(* Logix 5000 AddOnInstructionDefinition export Banner_B25_Param_v4; software revision 33.03; part 2 of 2 *)
(* tags used below, declared in another part *)
   B25 : Banner_B25_v4;
   Port_Data : Banner_IOL_Port_v4;
   Port : DINT;
   Local_Control : DINT;
   Command_Being_Processed : BOOL;
   Index_Write_Inprocess : INT;
   Inprocess_Index : DINT;
(* Banner_B25_Param_v4, continued *)

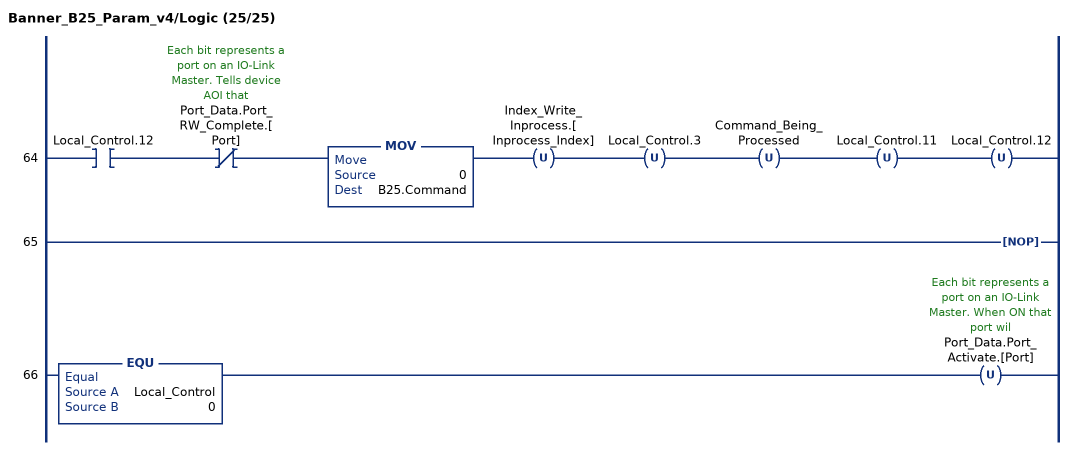
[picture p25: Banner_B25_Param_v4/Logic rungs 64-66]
   64: XIC(Local_Control.12)XIO(Port_Data.Port_RW_Complete.[Port])MOV(0,B25.Command)OTU(Index_Write_Inprocess.[Inprocess_Index])OTU(Local_Control.3)OTU(Command_Being_Processed)OTU(Local_Control.11)OTU(Local_Control.12);
   65: NOP();
   66: EQU(Local_Control,0)OTU(Port_Data.Port_Activate.[Port]);
END_ROUTINE
END_ADD_ON_INSTRUCTION
